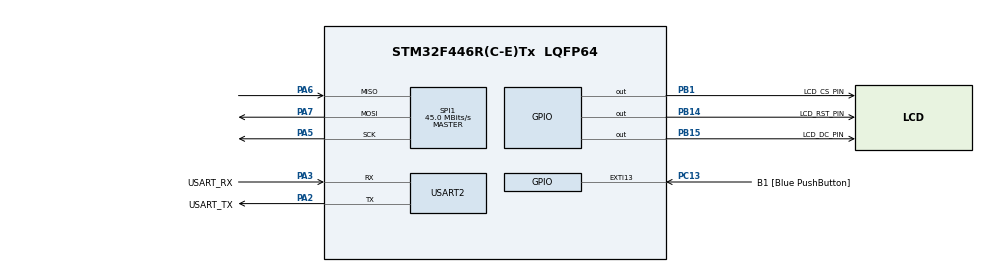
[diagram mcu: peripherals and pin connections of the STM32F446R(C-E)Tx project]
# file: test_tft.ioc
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Mcu.Family=STM32F4
Mcu.Name=STM32F446R(C-E)Tx
Mcu.Package=LQFP64
NVIC.PriorityGroup=NVIC_PRIORITYGROUP_0
PA13.GPIO_Label=TMS
PA13.Mode=Serial_Wire
PA13.Signal=SYS_JTMS-SWDIO
PA14.GPIO_Label=TCK
PA14.Mode=Serial_Wire
PA14.Signal=SYS_JTCK-SWCLK
PA2.GPIO_Label=USART_TX
PA2.Mode=Asynchronous
PA2.Signal=USART2_TX
PA3.GPIO_Label=USART_RX
PA3.Mode=Asynchronous
PA3.Signal=USART2_RX
PA5.Mode=Full_Duplex_Master
PA5.Signal=SPI1_SCK
PA6.Mode=Full_Duplex_Master
PA6.Signal=SPI1_MISO
PA7.Mode=Full_Duplex_Master
PA7.Signal=SPI1_MOSI
PB1.GPIO_Label=LCD_CS_PIN
PB1.Signal=GPIO_Output
PB14.GPIO_Label=LCD_RST_PIN
PB14.Signal=GPIO_Output
PB15.GPIO_Label=LCD_DC_PIN
PB15.Signal=GPIO_Output
PB3.GPIO_Label=SWO
PB3.Signal=SYS_JTDO-SWO
PC13.GPIO_Label=B1 [Blue PushButton]
PC13.GPIO_ModeDefaultEXTI=GPIO_MODE_IT_FALLING
PC13.Signal=GPXTI13
PC14-OSC32_IN.Mode=LSE-External-Oscillator
PC14-OSC32_IN.Signal=RCC_OSC32_IN
PC15-OSC32_OUT.Mode=LSE-External-Oscillator
PC15-OSC32_OUT.Signal=RCC_OSC32_OUT
PH0-OSC_IN.Mode=HSE-External-Oscillator
PH0-OSC_IN.Signal=RCC_OSC_IN
PH1-OSC_OUT.Mode=HSE-External-Oscillator
PH1-OSC_OUT.Signal=RCC_OSC_OUT
ProjectManager.HeapSize=0x200
ProjectManager.StackSize=0x400
ProjectManager.TargetToolchain=STM32CubeIDE
RCC.48MHZClocksFreq_Value=84000000
RCC.AHBFreq_Value=180000000
RCC.APB1CLKDivider=RCC_HCLK_DIV4
RCC.APB1Freq_Value=45000000
RCC.APB1TimFreq_Value=90000000
RCC.APB2CLKDivider=RCC_HCLK_DIV2
RCC.APB2Freq_Value=90000000
RCC.APB2TimFreq_Value=180000000
RCC.CortexFreq_Value=180000000
RCC.FLatency-AdvancedSettings=FLASH_LATENCY_5
RCC.HCLKFreq_Value=180000000
RCC.HSE_VALUE=8000000
RCC.HSI_VALUE=16000000
RCC.PLLM=8
RCC.PLLN=180
RCC.SYSCLKFreq_VALUE=180000000
RCC.SYSCLKSource=RCC_SYSCLKSOURCE_PLLCLK
RCC.USBFreq_Value=180000000
RCC.VCOOutputFreq_Value=360000000
SPI1.BaudRatePrescaler=SPI_BAUDRATEPRESCALER_2
SPI1.CalculateBaudRate=45.0 MBits/s
SPI1.Direction=SPI_DIRECTION_2LINES
SPI1.Mode=SPI_MODE_MASTER
SPI1.VirtualType=VM_MASTER
USART2.VirtualMode=VM_ASYNC
board=NUCLEO-F446RE

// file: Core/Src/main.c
/* USER CODE BEGIN Header */
/**
  ******************************************************************************
  * @file           : main.c
  * @brief          : Main program body
  ******************************************************************************
  * @attention
  *
<<<<<<< HEAD
  * Copyright (c) 2025 STMicroelectronics.
=======
  * Copyright (c) 2026 STMicroelectronics.
>>>>>>> d357943 (removed HAL completly from the ili lib exepct the hal delays)
  * All rights reserved.
  *
  * This software is licensed under terms that can be found in the LICENSE file
  * in the root directory of this software component.
  * If no LICENSE file comes with this software, it is provided AS-IS.
  *
  ******************************************************************************
  */
/* USER CODE END Header */
#include "main.h"

/* USER CODE BEGIN Includes */
<<<<<<< HEAD
#include "ILI9341_STM32_Driver.h"
#include "ILI9341_GFX.h"
=======
#include "ILI9341_GFX.h"
#include "ILI9341_STM32_Driver.h"
>>>>>>> d357943 (removed HAL completly from the ili lib exepct the hal delays)
/* USER CODE END Includes */

SPI_HandleTypeDef hspi1;

UART_HandleTypeDef huart2;

void SystemClock_Config(void);
static void MX_GPIO_Init(void);
static void MX_USART2_UART_Init(void);
static void MX_SPI1_Init(void);

int main(void)
{

  /* MCU Configuration--------------------------------------------------------*/

  /* Reset of all peripherals, Initializes the Flash interface and the Systick. */
  HAL_Init();

  /* Configure the system clock */
  SystemClock_Config();

  /* Initialize all configured peripherals */
  MX_GPIO_Init();
  MX_USART2_UART_Init();
  MX_SPI1_Init();
  /* USER CODE BEGIN 2 */
<<<<<<< HEAD
  // --- SCREEN TEST CODE START ---

   // 1. Initialize the display
  ILI9341_Init();

    // 2. Set the rotation
    ILI9341_Set_Rotation(SCREEN_HORIZONTAL_2);

    // 3. Fill the entire screen with BLACK.
    ILI9341_Fill_Screen(BLACK);
    HAL_Delay(500);

    // 4. Draw text
    ILI9341_Draw_Text("SYSTEM OK", 90, 20, WHITE, 3, BLACK);
    ILI9341_Draw_Text("F446RE RUNNING", 60, 60, GREEN, 2, BLACK);

    // 5. Draw shapes using the CORRECT function names
    ILI9341_Draw_Filled_Rectangle_Coord(20, 100, 220, 150, PINK); // Corrected function name
    ILI9341_Draw_Hollow_Circle(250, 125, 30, GREEN);              // Corrected function name
    ILI9341_Draw_Filled_Circle(80, 180, 40, WHITE);             // This function name was correct
=======
  ILI9341_Init();
  HAL_Delay(100);
  ILI9341_Draw_Colour(RED);
  ILI9341_Fill_Screen(RED);
  ILI9341_Draw_Text("bitch", 10,70, BLACK, 2, BLUE);
>>>>>>> d357943 (removed HAL completly from the ili lib exepct the hal delays)
  /* USER CODE END 2 */

  /* Infinite loop */
  while (1)
  {

  }
}

void SystemClock_Config(void)
{
  RCC_OscInitTypeDef RCC_OscInitStruct = {0};
  RCC_ClkInitTypeDef RCC_ClkInitStruct = {0};

  /** Configure the main internal regulator output voltage
  */
  __HAL_RCC_PWR_CLK_ENABLE();
<<<<<<< HEAD
  __HAL_PWR_VOLTAGESCALING_CONFIG(PWR_REGULATOR_VOLTAGE_SCALE3);
=======
  __HAL_PWR_VOLTAGESCALING_CONFIG(PWR_REGULATOR_VOLTAGE_SCALE1);
>>>>>>> d357943 (removed HAL completly from the ili lib exepct the hal delays)

  /** Initializes the RCC Oscillators according to the specified parameters
  * in the RCC_OscInitTypeDef structure.
  */
  RCC_OscInitStruct.OscillatorType = RCC_OSCILLATORTYPE_HSI;
  RCC_OscInitStruct.HSIState = RCC_HSI_ON;
  RCC_OscInitStruct.HSICalibrationValue = RCC_HSICALIBRATION_DEFAULT;
  RCC_OscInitStruct.PLL.PLLState = RCC_PLL_ON;
  RCC_OscInitStruct.PLL.PLLSource = RCC_PLLSOURCE_HSI;
  RCC_OscInitStruct.PLL.PLLM = 8;
<<<<<<< HEAD
  RCC_OscInitStruct.PLL.PLLN = 90;
=======
  RCC_OscInitStruct.PLL.PLLN = 180;
>>>>>>> d357943 (removed HAL completly from the ili lib exepct the hal delays)
  RCC_OscInitStruct.PLL.PLLP = RCC_PLLP_DIV2;
  RCC_OscInitStruct.PLL.PLLQ = 2;
  RCC_OscInitStruct.PLL.PLLR = 2;
  if (HAL_RCC_OscConfig(&RCC_OscInitStruct) != HAL_OK)
  {
    Error_Handler();
  }

<<<<<<< HEAD
=======
  /** Activate the Over-Drive mode
  */
  if (HAL_PWREx_EnableOverDrive() != HAL_OK)
  {
    Error_Handler();
  }

>>>>>>> d357943 (removed HAL completly from the ili lib exepct the hal delays)
  /** Initializes the CPU, AHB and APB buses clocks
  */
  RCC_ClkInitStruct.ClockType = RCC_CLOCKTYPE_HCLK|RCC_CLOCKTYPE_SYSCLK
                              |RCC_CLOCKTYPE_PCLK1|RCC_CLOCKTYPE_PCLK2;
  RCC_ClkInitStruct.SYSCLKSource = RCC_SYSCLKSOURCE_PLLCLK;
  RCC_ClkInitStruct.AHBCLKDivider = RCC_SYSCLK_DIV1;
<<<<<<< HEAD
  RCC_ClkInitStruct.APB1CLKDivider = RCC_HCLK_DIV2;
  RCC_ClkInitStruct.APB2CLKDivider = RCC_HCLK_DIV1;

  if (HAL_RCC_ClockConfig(&RCC_ClkInitStruct, FLASH_LATENCY_2) != HAL_OK)
=======
  RCC_ClkInitStruct.APB1CLKDivider = RCC_HCLK_DIV4;
  RCC_ClkInitStruct.APB2CLKDivider = RCC_HCLK_DIV2;

  if (HAL_RCC_ClockConfig(&RCC_ClkInitStruct, FLASH_LATENCY_5) != HAL_OK)
>>>>>>> d357943 (removed HAL completly from the ili lib exepct the hal delays)
  {
    Error_Handler();
  }
}

static void MX_SPI1_Init(void)
{

  /* SPI1 parameter configuration*/
  hspi1.Instance = SPI1;
  hspi1.Init.Mode = SPI_MODE_MASTER;
  hspi1.Init.Direction = SPI_DIRECTION_2LINES;
  hspi1.Init.DataSize = SPI_DATASIZE_8BIT;
  hspi1.Init.CLKPolarity = SPI_POLARITY_LOW;
  hspi1.Init.CLKPhase = SPI_PHASE_1EDGE;
  hspi1.Init.NSS = SPI_NSS_SOFT;
<<<<<<< HEAD
  hspi1.Init.BaudRatePrescaler = SPI_BAUDRATEPRESCALER_4;
=======
  hspi1.Init.BaudRatePrescaler = SPI_BAUDRATEPRESCALER_2;
>>>>>>> d357943 (removed HAL completly from the ili lib exepct the hal delays)
  hspi1.Init.FirstBit = SPI_FIRSTBIT_MSB;
  hspi1.Init.TIMode = SPI_TIMODE_DISABLE;
  hspi1.Init.CRCCalculation = SPI_CRCCALCULATION_DISABLE;
  hspi1.Init.CRCPolynomial = 10;
  if (HAL_SPI_Init(&hspi1) != HAL_OK)
  {
    Error_Handler();
  }

}

static void MX_USART2_UART_Init(void)
{

  huart2.Instance = USART2;
  huart2.Init.BaudRate = 115200;
  huart2.Init.WordLength = UART_WORDLENGTH_8B;
  huart2.Init.StopBits = UART_STOPBITS_1;
  huart2.Init.Parity = UART_PARITY_NONE;
  huart2.Init.Mode = UART_MODE_TX_RX;
  huart2.Init.HwFlowCtl = UART_HWCONTROL_NONE;
  huart2.Init.OverSampling = UART_OVERSAMPLING_16;
  if (HAL_UART_Init(&huart2) != HAL_OK)
  {
    Error_Handler();
  }

}

static void MX_GPIO_Init(void)
{
  GPIO_InitTypeDef GPIO_InitStruct = {0};

  /* GPIO Ports Clock Enable */
  __HAL_RCC_GPIOC_CLK_ENABLE();
  __HAL_RCC_GPIOH_CLK_ENABLE();
  __HAL_RCC_GPIOA_CLK_ENABLE();
  __HAL_RCC_GPIOB_CLK_ENABLE();

  /*Configure GPIO pin Output Level */
<<<<<<< HEAD
  HAL_GPIO_WritePin(LCD_CS_GPIO_Port, LCD_CS_Pin, GPIO_PIN_RESET);

  /*Configure GPIO pin Output Level */
  HAL_GPIO_WritePin(LCD_RST_GPIO_Port, LCD_RST_Pin, GPIO_PIN_RESET);

  /*Configure GPIO pin Output Level */
  HAL_GPIO_WritePin(LCD_DC_GPIO_Port, LCD_DC_Pin, GPIO_PIN_RESET);
=======
  HAL_GPIO_WritePin(GPIOB, LCD_CS_PIN_Pin|LCD_RST_PIN_Pin|LCD_DC_PIN_Pin, GPIO_PIN_RESET);
>>>>>>> d357943 (removed HAL completly from the ili lib exepct the hal delays)

  /*Configure GPIO pin : B1_Pin */
  GPIO_InitStruct.Pin = B1_Pin;
  GPIO_InitStruct.Mode = GPIO_MODE_IT_FALLING;
  GPIO_InitStruct.Pull = GPIO_NOPULL;
  HAL_GPIO_Init(B1_GPIO_Port, &GPIO_InitStruct);

<<<<<<< HEAD
  /*Configure GPIO pin : LCD_CS_Pin */
  GPIO_InitStruct.Pin = LCD_CS_Pin;
  GPIO_InitStruct.Mode = GPIO_MODE_OUTPUT_PP;
  GPIO_InitStruct.Pull = GPIO_NOPULL;
  GPIO_InitStruct.Speed = GPIO_SPEED_FREQ_LOW;
  HAL_GPIO_Init(LCD_CS_GPIO_Port, &GPIO_InitStruct);

  /*Configure GPIO pin : LCD_RST_Pin */
  GPIO_InitStruct.Pin = LCD_RST_Pin;
  GPIO_InitStruct.Mode = GPIO_MODE_OUTPUT_PP;
  GPIO_InitStruct.Pull = GPIO_NOPULL;
  GPIO_InitStruct.Speed = GPIO_SPEED_FREQ_LOW;
  HAL_GPIO_Init(LCD_RST_GPIO_Port, &GPIO_InitStruct);

  /*Configure GPIO pin : LCD_DC_Pin */
  GPIO_InitStruct.Pin = LCD_DC_Pin;
  GPIO_InitStruct.Mode = GPIO_MODE_OUTPUT_PP;
  GPIO_InitStruct.Pull = GPIO_NOPULL;
  GPIO_InitStruct.Speed = GPIO_SPEED_FREQ_LOW;
  HAL_GPIO_Init(LCD_DC_GPIO_Port, &GPIO_InitStruct);
=======
  /*Configure GPIO pins : LCD_CS_PIN_Pin LCD_RST_PIN_Pin LCD_DC_PIN_Pin */
  GPIO_InitStruct.Pin = LCD_CS_PIN_Pin|LCD_RST_PIN_Pin|LCD_DC_PIN_Pin;
  GPIO_InitStruct.Mode = GPIO_MODE_OUTPUT_PP;
  GPIO_InitStruct.Pull = GPIO_NOPULL;
  GPIO_InitStruct.Speed = GPIO_SPEED_FREQ_LOW;
  HAL_GPIO_Init(GPIOB, &GPIO_InitStruct);
>>>>>>> d357943 (removed HAL completly from the ili lib exepct the hal delays)

}

void Error_Handler(void)
{
  __disable_irq();
  while (1)
  {
  }
}
